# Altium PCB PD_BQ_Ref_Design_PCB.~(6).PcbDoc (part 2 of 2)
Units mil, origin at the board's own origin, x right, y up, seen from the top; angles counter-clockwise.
Board outline 2000 x 3000 mil, 4 copper layers (Top Layer, Signal Layer 1, Signal Layer 2, Bottom Layer), stack 61.2 mil thick; 108 components, 54 nets, 333 pads, 494 vias.
Unrouted connection lines stored in the file: 228.

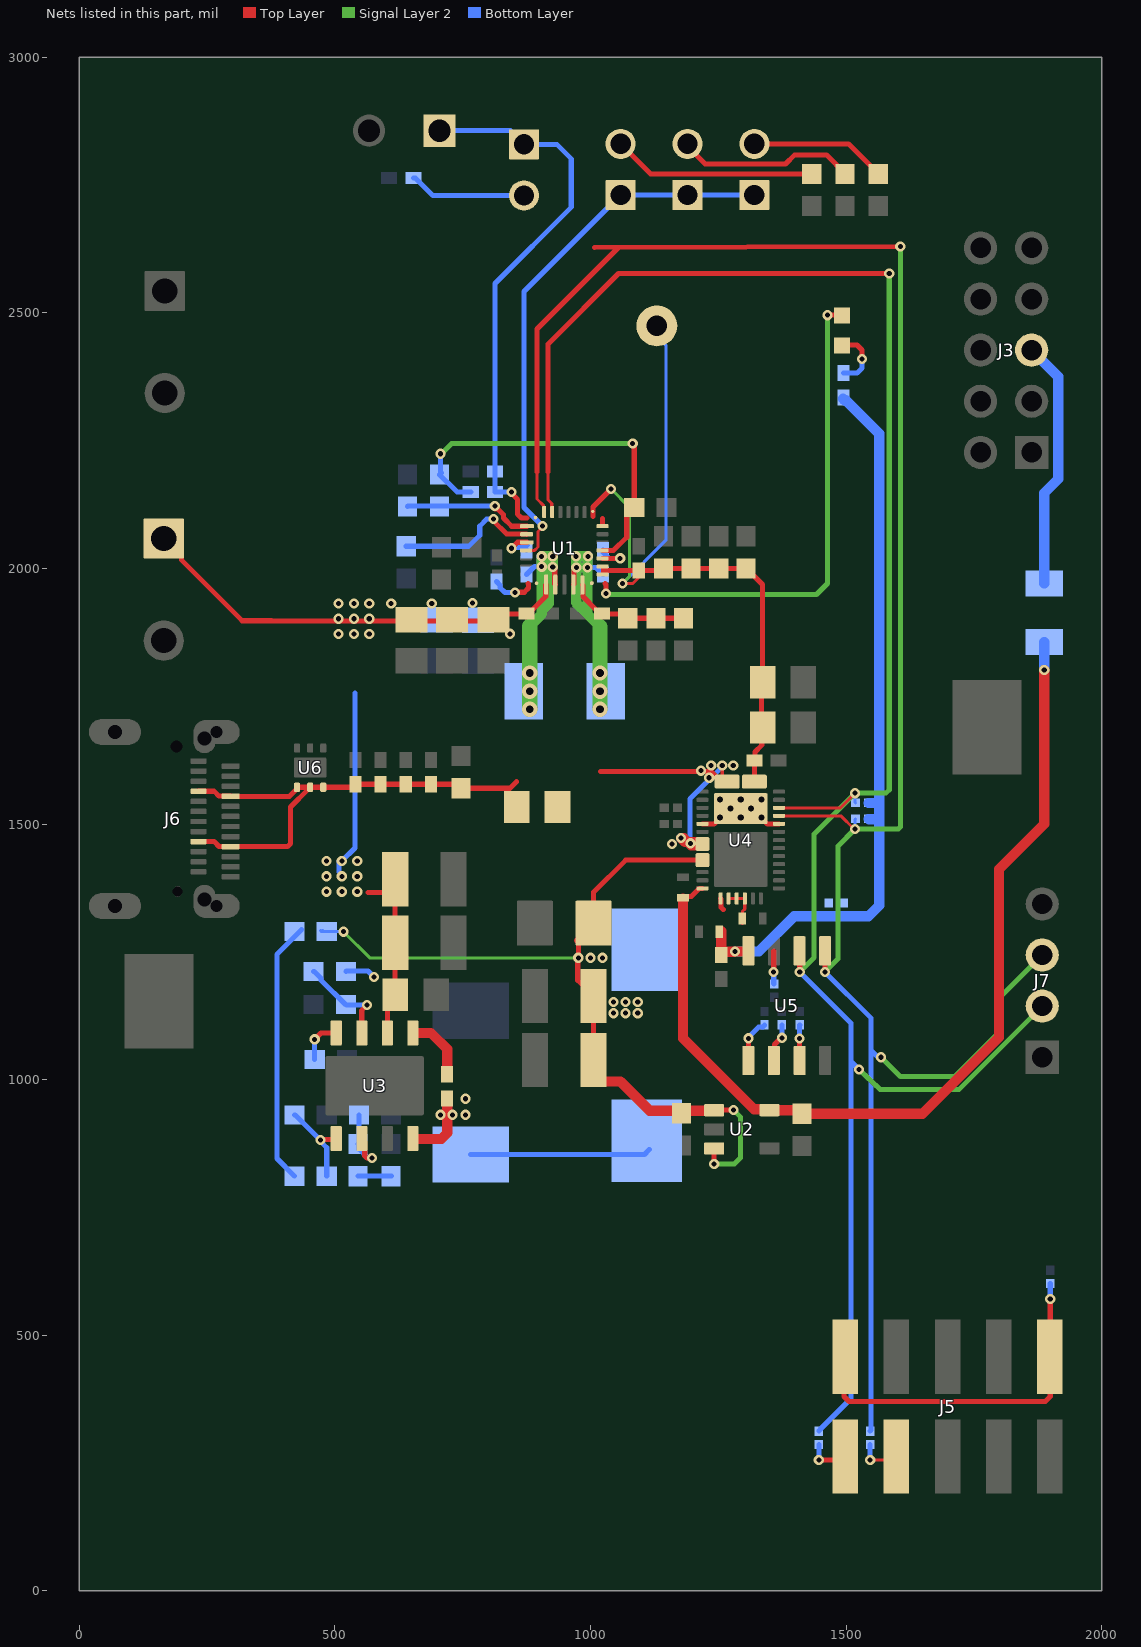
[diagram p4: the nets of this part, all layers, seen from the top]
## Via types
v1: diameter 20, hole 10, Top Layer to Bottom Layer, tented both sides, 445 vias
v2: diameter 23.62, hole 11.81, Top Layer to Bottom Layer, tented both sides, 24 vias
v3: diameter 30, hole 15, Top Layer to Bottom Layer, tented both sides, 12 vias
v4: diameter 19.68, hole 7.87, Top Layer to Bottom Layer, tented both sides, 10 vias
v5: diameter 20, hole 10, Top Layer to Bottom Layer, 3 vias

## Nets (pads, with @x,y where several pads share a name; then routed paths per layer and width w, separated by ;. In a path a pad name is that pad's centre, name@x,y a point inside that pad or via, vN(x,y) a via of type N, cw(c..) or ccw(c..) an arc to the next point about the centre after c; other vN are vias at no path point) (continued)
I2C_SCL: J7.2 R21.1 R24.2 R26.1 U1.14 U4.17 U5.6 | length 4180.7
  Top Layer w6: 917.32,2188.98 917.32,2133.86 924.38,2126.8 924.38,2111.07 U1.14@925.31,2110.14 ; U4.17@1368.91,1531.68 1489.12,1531.68 v1(1517.72,1560.27)
  Top Layer w10: 917.32,2188.98 917.32,2438.98 1055.12,2576.77 v1(1584.65,2576.77) ; v1(1409.45,1210.63) U5.6@1409.45,1251.5
  Signal Layer 2 w10: v1(1409.45,1210.63) 1437.32,1238.5 1437.32,1479.88 v1(1517.72,1560.27) 1577.99,1560.27 1584.65,1566.93 v1(1584.65,2576.77) ; v1(1525.59,1019.68) 1566.93,980.32 1720.47,980.32 J7.2@1883.86,1143.7
  Bottom Layer w6: v1(1517.72,1560.27) 1517.72,1542.13 R24.2@1518.5,1541.34
  Bottom Layer w10: v1(1409.45,1210.63) 1509.84,1110.24 1509.84,1033.46 ; R26.1@1446.85,312.2 1446.85,312.99 1450.12,316.26 1450.21,316.26 1509.84,375.9 1509.84,1033.46 ; v1(1525.59,1019.68) 1511.81,1033.46 1509.84,1033.46
I2C_SDA: J7.3 R22.1 R25.2 R27.1 U1.15 U4.16 U5.5 | length 4366.5
  Top Layer w6: 895.67,2188.98 895.67,2135.83 908.63,2122.87 908.63,2111.07 U1.15@909.57,2110.14 ; U4.16@1368.91,1515.93 1489.98,1515.93 1515.75,1490.16 v1(1517.72,1490.16)
  Top Layer w10: 895.67,2188.98 895.67,2468.5 1055.12,2627.95 ; 1007.87,2627.95 v1@1604.33,2629.92 ; v1(1458.66,1210.63) U5.5@1458.66,1251.5
  Signal Layer 2 w10: v1(1458.66,1210.63) 1484.25,1236.22 1484.25,1456.69 v1(1517.72,1490.16) 1602.36,1490.16 1606.3,1494.09 v1(1606.3,2629.92) ; v1(1568.5,1043.7) 1606.3,1005.91 1712.6,1005.91 1797.24,1090.55 1797.24,1157.09 J7.3@1883.86,1243.7
  Bottom Layer w6: v1(1517.72,1490.16) 1517.72,1509.05 R25.2@1518.5,1509.84
  Bottom Layer w10: v1(1458.66,1210.63) 1549.21,1120.08 1549.21,1057.09 ; R27.1@1547.24,312.2 1549.21,314.17 1549.21,1057.09 ; v1(1568.5,1043.7) 1562.6,1043.7 1549.21,1057.09
ILIM_HIZ: R4.1 R6.2 U1.17 | length 265.7
  Top Layer w10: v1@818.44,2116.46 812.99,2116.46 v1(812.99,2122.04) 830.16,2104.88 830.16,2098.5 846.08,2082.58 U1.17@876.1,2082.58
  Bottom Layer w10: R6.2@641.92,2121.06 642.9,2122.05 802.68,2122.05 v1(812.99,2122.04)
LDO_1V5: C37.1 U4.2 U4.3 U4.4 | length 83
  Top Layer w6: U4.2@1270.48,1354.51 U4.3@1286.23,1354.51 U4.4@1301.98,1354.51 1301.98,1333.47 1297.24,1328.74 1297.24,1305.43 C37.1@1296.93,1305.12
LDO_3V3: C36.1 C43.1 R2.2 R21.2 R22.2 R24.1 R25.1 U4.1 U5.8 | length 1507.2
  Top Layer w10: U4.1@1254.73,1354.51 1255.8,1353.45 1255.8,1336.72 1259.84,1332.68
  Top Layer w20: C43.1@1255.91,1244.09 1255.91,1248.03 C43.1@1257.72,1249.84 ; C36.1@1255.91,1290.2 1255.91,1249.84 C43.1@1257.72,1249.84 ; U5.8@1309.05,1251.89 1307.79,1250.63 v1(1282.76,1250.63) 1282.13,1250 1269.43,1250 1269.27,1249.84 C43.1@1257.72,1249.84
  Bottom Layer w20: v1@1283.46,1250.63 1329.37,1250.63 1398.43,1319.69 1468.5,1319.69 1498.03,1319.69 1527.56,1319.69 1544.09,1319.69 1564.96,1340.55 1564.96,1509.35 ; R2.2@1494.09,2331.69 1496.89,2328.9 1499.84,2328.9 1564.96,2263.78 1564.96,1541.91 ; R25.1@1544.49,1509.84 1544.98,1509.35 1564.96,1509.35 ; R24.1@1544.49,1541.34 1564.39,1541.34 1564.96,1541.91 ; 1564.96,1509.35 1564.96,1541.91
NetC1_1: C1.1 U1.4 | length 76.9
  Top Layer w10: U1.4@1023.74,2019.59 1058.09,2019.59 v1(1058.19,2019.69)
  Bottom Layer w10: C1.1@1024.72,2035.43 1024.72,2031.5 1036.64,2019.59 1058.09,2019.59 v1(1058.19,2019.69)
NetC1_2: C1.2 L1.1 U1.28 | length 640.5
  Top Layer w10: U1.28@966.65,1968.4 967.72,1969.47 967.72,1997.24 v1(972.44,2001.97)
  Signal Layer 2 w20: 1018.82,1885.83 994.42,1910.22 ; v1(972.44,2001.97) 972.44,2022.76 v1(971.57,2023.62) v1(995.2,2023.62) 994.09,2022.52 v1(994.09,2001.97) ; v1(972.44,2001.97) v1(994.09,2001.97) ; v1(972.44,2001.97) 972.44,1933.97 971.56,1933.09 994.42,1910.22 ; v1(994.09,2001.97) 994.42,2001.64 994.42,1910.22
  Signal Layer 2 w30: v3(1018.82,1724.41) 1018.82,1885.83
  Bottom Layer w10: v1(994.09,2001.97) 1010.94,2001.97 C1.2@1024.72,1988.19
  Bottom Layer w20: v1@971.57,2003.74 972.44,2002.87 v1(972.44,2001.97) v1(994.09,2001.97) 994.09,2022.52 v1(995.2,2023.62) v1(971.57,2023.62) v1@971.57,2003.74
  other v3: 1018.82,1759.84 1018.82,1795.44
NetC7_1: C7.1 U1.19 | length 77
  Top Layer w10: v1(845.59,2039.37) 857.3,2051.08 U1.19@875.71,2051.08
  Bottom Layer w10: v1(845.59,2039.37) 847.09,2040.87 869.68,2040.87 C7.1@875.12,2035.43 ; C7.1@870.35,2039.37 C7.1@877.17,2046.18
NetC7_2: C7.2 L1.2 U1.26 | length 624.4
  Top Layer w10: v1(926.3,2002.54) 926.3,2001.23 930.16,1997.37 930.16,1969.47 U1.26@931.22,1968.4
  Signal Layer 2 w20: 881.02,1887.04 904.65,1910.67 v1(904.65,2003.36) 925.47,2003.36 v1(926.3,2002.54) ; 904.65,1917.32 918.43,1931.1 918.43,1994.66 v1(926.3,2002.54) ; v1@904.65,2004.35 v1(904.65,2023.62) v1(926.3,2023.62) v1(926.3,2002.54)
  Signal Layer 2 w30: v3(881.02,1724.41) v3(881.02,1759.84) v3(881.02,1795.3) 881.02,1887.04
  Bottom Layer w10: C7.2@875.12,1988.19 890.87,2003.94 891.44,2003.36 v1(904.65,2003.36)
  Bottom Layer w20: v1(904.65,2003.36) 925.47,2003.36 v1(926.3,2002.54) v1(926.3,2023.62) v1(904.65,2023.62) v1(904.65,2003.36)
NetC22_1: C22.1 U1.24 | length 87.7
  Top Layer w10: v1(852.36,1952.76) 853.01,1953.4 870.73,1953.4 878.91,1961.58 878.91,1969.52 877.95,1970.47
  Bottom Layer w10: C22.1@816.06,1974.41 822.87,1967.6 822.87,1962.55 832.67,1952.76 v1(852.36,1952.76)
NetC25_1: C25.1 U3.1 | length 129.4
  Top Layer w20: U3.1@652.76,1091.26 688.27,1091.26 719.74,1059.78 C25.1@719.74,1010.38
NetC25_2: C25.2 D2.1 L2.1 U3.8 | length 493.1
  Top Layer w20: U3.8@652.76,884.57 652.87,884.57 653.58,883.86 708.03,883.86 719.74,895.57 C25.2@719.74,963.14
  Bottom Layer w10: D2.1@765.75,853.6 1105.57,853.6 L2.1@1115.16,863.19
  other v1: 706.69,931.1 730.32,931.1 755.91,931.1 755.91,962.6
NetC32_1: C32.1 C34.1 U3.6 | length 164.6
  Top Layer w10: U3.6@552.76,884.57 558.58,878.74 558.58,850.87 562.99,846.46 v1(572.83,846.46)
  Bottom Layer w10: C32.1@546.79,874.02 C32.1@546.79,872.56 ; C34.1@547.24,931.1 547.24,875.98 C32.1@545.28,874.02 C32.1@546.79,872.56 ; C32.1@547.98,864.41 549.51,869.93 C32.1@546.79,872.56 ; v1(572.83,846.46) 565.06,846.46 546.79,864.74 C32.1@546.79,872.56
NetC32_2: C32.2 R17.2 | length 65.9
  Bottom Layer w10: C32.2@545.28,811.02 R17.2@611.22,811.02
NetC33_1: C33.1 U3.4 | length 86.7
  Top Layer w10: v1(460.63,1078.74) 473.15,1091.26 U3.4@502.76,1091.26
  Bottom Layer w10: C33.1@460.63,1039.37 v1(460.63,1078.74)
NetC44_1: C44.1 C45.2 C46.2 C47.2 C48.2 J6.A4 J6.A9 J6.B4 J6.B9 L3.1 U6.4 U6.5 U6.6 | length 961.1
  Top Layer w10: J6.B4@233.27,1465.55 264.02,1465.55 273.54,1456.02 295.94,1456.02 J6.A9@296.26,1455.71 311.38,1455.71 407.53,1455.71 413.39,1461.57 413.39,1533.46 447.91,1567.99 450.87,1567.99 451.77,1568.9 U6.5@451.77,1571.85 ; J6.B9@233.27,1563.98 264.02,1563.98 273.54,1554.45 295.94,1554.45 J6.A4@296.26,1554.13 411.42,1554.13 426.18,1568.9 U6.4@426.18,1571.85 447.91,1571.85 U6.5@451.77,1571.85 ; 855.67,1582.68 842.87,1569.88 C44.1@747.05,1569.88 739.17,1577.76 C48.2@687.99,1577.76 C47.2@638.78,1577.76 C46.2@589.57,1577.76 C45.2@540.35,1577.76 534.45,1571.85 U6.6@477.36,1571.85 U6.5@451.77,1571.85
NetD1_1: D1.1 R2.1 | length 119.8
  Top Layer w10: D1.1@1492.13,2436.02 1493.11,2437.01 1521.65,2437.01 1531.5,2427.17 v1(1531.5,2409.45)
  Bottom Layer w10: R2.1@1495.08,2381.89 1521.65,2381.89 1531.5,2391.73 v1(1531.5,2409.45)
NetJ3_5: J3.5 R11.1 | length 489.2
  Bottom Layer w20: J3.5@1863.19,2426.97 1915,2375.16 1915,2174.84 1887.8,2147.64 R11.1@1887.8,1970.47
NetJ5_1: J5.1 R26.2 | length 85
  Top Layer w10: v1(1446.85,255.91) 1491.67,255.91 J5.1@1498.64,262.87
  Bottom Layer w10: v1(1446.85,255.91) R26.2@1446.85,286.22
NetJ5_2: J5.2 J5.10 R29.2 | length 712.5
  Top Layer w10: J5.2@1498.64,457.75 1496.16,455.27 1496.16,379.83 1505.91,370.08 1889.76,370.08 1899.51,379.83 1899.51,456.88 J5.10@1898.64,457.75 1899.61,458.72 v1(1899.61,570.87)
  Bottom Layer w10: v1(1899.61,570.87) R29.2@1899.61,601.18
NetJ5_3: J5.3 R27.2 | length 84.6
  Top Layer w6: v1(1547.24,255.91) 1591.67,255.91 J5.3@1598.64,262.87
  Bottom Layer w10: v1(1547.24,255.91) R27.2@1547.24,286.22
NetJP1_2: JP1.2 R8.2 | length 398.4
  Top Layer w10: JP1.2@1059.06,2830.51 1117.91,2771.65 R8.2@1433.07,2771.65
NetJP2_2: JP2.2 R9.2 | length 350.8
  Top Layer w10: JP2.2@1189.96,2830.51 1189.96,2825.79 1224.76,2790.98 1381.73,2790.98 1399.81,2809.06 1461.61,2809.06 1498.03,2772.64 R9.2@1498.03,2771.65
NetJP3_2: JP3.2 R10.2 | length 267.1
  Top Layer w10: JP3.2@1320.87,2830.51 1505.12,2830.51 1562.99,2772.64 R10.2@1562.99,2771.65
NetJP4_2: JP4.2 R7.2 | length 230.7
  Bottom Layer w10: R7.2@653.54,2763.78 657.48,2763.78 691.73,2729.53 JP4.2@870.08,2729.53
NetR1_2: R1.2 U1.18 | length 281.9
  Top Layer w10: v1(810.16,2096.46) 810.16,2093.39 835.97,2067.58 874.37,2067.58 U1.18@875.12,2066.83
  Bottom Layer w10: R1.2@639.76,2043.31 761.81,2043.31 783.46,2064.96 783.46,2082.58 783.41,2082.63 797.24,2096.46 v1(810.16,2096.46)
NetR12_1: R12.1 R14.2 | length 516.5
  Bottom Layer w10: R14.2@421.26,811.02 386.81,845.47 386.81,1245.08 R12.1@435.04,1293.31
NetR13_1: R13.1 R15.2 U3.3 | length 192.6
  Top Layer w10: U3.3@552.76,1091.26 552.76,1135.43 v1(562.99,1145.67)
  Bottom Layer w10: R13.1@458.66,1211.61 459.65,1211.61 473.35,1197.91 473.35,1193.98 520.67,1146.65 R15.2@521.65,1146.65 522.64,1145.67 v1(562.99,1145.67)
NetR14_1: R14.1 R16.2 U3.5 | length 179
  Top Layer w10: v1(471.95,881.89) 472.82,882.77 500.95,882.77 U3.5@502.76,884.57
  Bottom Layer w10: R16.2@421.26,931.1 422.24,931.1 471.46,881.89 v1(471.95,881.89) 471.95,879.18 484.25,866.88 R14.1@484.25,811.02
NetR28_2: R28.2 | length 65.4
  Top Layer w10: v1(1358.27,1210.63) 1358.66,1211.02 1358.66,1251.5 1359.05,1251.89
  Bottom Layer w10: v1(1358.27,1210.63) 1358.76,1210.14 1358.76,1187.7 R28.2@1359.25,1187.2
NetR30_2: R30.2 U5.1 | length 87.4
  Top Layer w10: U5.1@1309.05,1037.33 v1(1309.06,1080.71)
  Bottom Layer w10: v1(1309.06,1080.71) 1309.06,1082.68 1329.41,1103.03 1337.28,1103.03 1340.55,1106.3 R30.2@1340.55,1107.09
NetR31_2: R31.2 U5.2 | length 76.5
  Top Layer w10: U5.2@1359.05,1037.33 1360.24,1038.51 1360.24,1068.9 1373.03,1081.69 v1(1375,1081.69)
  Bottom Layer w10: v1@1374.51,1082.18 R31.2@1374.51,1106.59
NetR32_2: R32.2 U5.3 | length 69.9
  Top Layer w10: U5.3@1409.05,1037.33 1409.14,1037.42 1409.14,1080.42 v1(1409.23,1080.51)
  Bottom Layer w10: v1(1409.23,1080.51) 1409.34,1080.62 1409.34,1106.98 R32.2@1409.45,1107.09
NetU4_15: U4.15 U4.30 U4.40 | length 233.7
  Top Layer w10: U4.30@1219.3,1500.18 1242.13,1500.18 U4.40@1272.06,1530.1 ; U4.40@1254.14,1512.19 U4.40@1272.06,1530.1 ; U4.15@1368.91,1500.18 1346.07,1500.18 ; U4.40@1272.06,1530.1 v2(1274.02,1530.1) U4.40@1294.1,1530.1 v2(1314.18,1530.1) 1316.15,1530.1 1346.07,1500.18 ; 1346.07,1500.18 1334.06,1512.19 1346.07,1500.18
  other v2: 1253.95,1512.39 1294.1,1512.39 1334.26,1512.39 1253.95,1547.82 1294.1,1547.82 1334.26,1547.82
P3V3: C24.2 C35.1 R11.2 U2.5 U4.38 | length 1869
  Top Layer w10: C35.1@1181.1,1355.98 1183.6,1358.48 1197.84,1358.48 1213.55,1374.2 U4.38@1219.3,1374.2
  Top Layer w20: C35.1@1181.1,1354.33 1181.1,1080.71 1319.94,941.87 1348.58,941.87 U2.5@1350.39,940.06 ; U2.5@1352.2,940.06 1406.67,940.06 C24.2@1413.55,933.17 1649.7,933.17 1799.21,1082.68 1799.21,1411.42 1887.8,1500 v1(1887.8,1801.18)
  Bottom Layer w20: v1(1887.8,1801.18) R11.2@1887.8,1856.3
PMID: C8.2 C9.2 C10.2 C11.1 U1.29 | length 238.5
  Top Layer w10: U1.29@984.37,1967.42 985.28,1966.51 985.28,1944.96 1012.01,1918.23 1012.01,1916.26 1017.83,1910.43 1065.08,1910.43 C10.2@1072.95,1902.56 C9.2@1128.07,1902.56 C8.2@1182.2,1902.56
PP5V: C23.2 C26.1 C27.1 C28.1 L2.2 R12.2 U2.1 U2.3 U4.34-35 | length 1669.2
  Top Layer w10: C28.1@1005.91,1038.39 1006.3,1038.78 1006.3,1163.39 975.32,1194.37 975.32,1237.13 v1(976.38,1238.19) 976.38,1268.31 972.44,1272.24 C26.1@1006.3,1306.1 ; C26.1@1023.03,1289.37 C26.1@1006.3,1306.1 ; U4.34-35@1219.3,1429.31 1069.08,1429.31 1006.3,1366.54 C26.1@1006.3,1306.1 ; v1(1242.13,834.65) U2.3@1242.13,865.25 ; U2.1@1242.13,940.06 1242.29,940.22 1279.99,940.22 v1(1280.16,940.39)
  Top Layer w20: C28.1@1005.91,1038.39 1005.91,1011.65 1021.5,996.06 1059.06,996.06 1116.14,938.98 1173.32,938.98 C23.2@1178.15,934.15 1182.98,938.98 1241.05,938.98 U2.1@1242.13,940.06
  Signal Layer 2 w6: v1(516.96,1289.37) 568.14,1238.19 v1(976.38,1238.19)
  Signal Layer 2 w10: v1(1242.13,834.65) 1281.5,834.65 1293.31,846.46 1293.31,927.17 1280.16,940.31 v1(1280.16,940.39)
  Bottom Layer w6: R12.2@472.44,1291.34 474.41,1289.37 476.38,1291.34 478.35,1289.37 v1(516.96,1289.37)
  other v1: 1045.28,1129.92 1068.9,1129.92 1092.52,1129.92 1045.28,1151.57 1068.9,1151.57 1092.52,1151.57 1000,1238.19 1023.62,1238.19
PPHV: C2.2 C3.2 C4.2 C5.2 C6.1 C38.1 C39.1 C40.1 TP1.1 U1.2 U1.3 U1.8 U1.9 U4.20-21-22 | length 1633.6
  Top Layer w6: 1022.76,2098.43 1023.74,2097.44 ; U1.2@1023.74,1988.09 1023.74,1996.06 U1.3@1023.74,2003.84 ; v1(1062.99,1970.47) 1082.8,1970.47 1101.5,1989.17 C6.1@1094.61,1996.06
  Top Layer w10: 1005.04,2101.41 1005.04,2120.08 ; U1.9@1005.04,2111.61 1005.04,2120.08 ; U1.8@1023.74,2084.65 1023.74,2097.44 ; 1026.69,1996.06 1049.59,1996.06 1049.9,1995.75 1066.47,1995.75 1066.79,1996.06 C6.1@1094.61,1996.06 1138.9,1996.06 C5.2@1142.83,2000 C4.2@1196.97,2000 C3.2@1251.1,2000 1305.24,2000 1336.78,1968.46 1336.78,1799.14 1334.98,1797.34 1334.98,1712.36 1336.78,1710.56 1335.27,1709.04 1335.27,1654.17 1322.06,1640.96 1322.06,1621.33 1320.74,1620 U4.20-21-22@1320.74,1582.86 ; v1(1040.47,2155.51) 1005.04,2120.08
  Signal Layer 2 w6: v1(1040.47,2155.51) 1076.19,2119.8 1076.19,1983.67 v1(1062.99,1970.47)
  Bottom Layer w6: v1(1062.99,1970.47) 1147.64,2055.12 1147.64,2436.67 1129.92,2454.39 TP1.1@1129.92,2474.41
PROG: JP1.1 JP2.1 JP3.1 U1.20 | length 1073.5
  Top Layer w6: U1.20@874.13,2035.33 890.9,2035.33 897.39,2041.83 897.39,2072.16 906.44,2081.21 v1(906.44,2082.85)
  Bottom Layer w10: v1(906.44,2082.85) 870.08,2119.21 870.08,2541.54 JP1.1@1059.06,2730.51 JP2.1@1189.96,2730.51 JP3.1@1320.87,2730.51
REGN: C18.1 R3.2 R4.2 U1.5 | length 752.8
  Top Layer w10: U1.5@1023.74,2035.33 1045.41,2035.33 1071.06,2060.99 1071.06,2105.39 1084.76,2119.09 C18.1@1085.75,2119.09 1085.75,2241.02 v1(1082.68,2244.09)
  Signal Layer 2 w10: v1(706.69,2224.41) 708.66,2224.41 728.35,2244.09 v1(1082.68,2244.09)
  Bottom Layer w10: R4.2@704.78,2184.06 R4.2@704.78,2183.07 ; v1(706.69,2224.41) 706.69,2188.92 708.66,2186.96 R4.2@704.78,2183.07 ; R3.2@765.87,2149.61 739.29,2149.61 719.53,2169.37 718.48,2169.37 R4.2@704.78,2183.07
STAT: D1.2 U1.1 | length 1022.6
  Top Layer w10: 1028.73,1970.41 1030.64,1968.49 v1(1030.64,1950.82) ; v1(1463.93,2495.43) 1488.83,2495.43 D1.2@1492.13,2492.13
  Signal Layer 2 w10: v1(1030.64,1950.82) 1032.56,1948.91 1039.63,1948.91 1039.72,1948.82 1442.32,1948.82 1463.93,1970.42 v1@1463.93,2500
SYS: C12.1 C13.1 C14.1 C15.1 C16.1 C17.1 C29.1 C30.1 C31.1 J1.1 R13.2 U1.25 U3.2 | length 1655.4
  Top Layer w10: J1.1@165.35,2058.66 199.72,2024.29 199.72,2016.81 318.9,1897.64 376.08,1897.64 376.44,1897.28 493.23,1897.28 507.4,1897.28 537.4,1897.28 v1@573.94,1897.28 ; 564.96,1366.14 C29.1@618.11,1366.14 ; v1@567.4,1897.28 v1@573.94,1897.28 ; U3.2@602.76,1091.26 602.76,1150.52 C31.1@618.28,1166.04 618.11,1166.21 C30.1@618.11,1267.72 ; C30.1@614.17,1271.65 C30.1@618.11,1267.72 ; C29.1@618.11,1391.73 C29.1@618.11,1366.14 ; U1.25@913.5,1968.4 912.6,1967.5 912.6,1944.96 888.82,1921.18 878.07,1910.43 827.24,1910.43 814.09,1897.28 733.39,1897.28 653.66,1897.28 v1@573.94,1897.28 ; C30.1@618.11,1267.72 C29.1@618.11,1366.14
  Bottom Layer w10: 508,1406 v1@508,1427.64 ; v1(513.78,1427.64) 539.37,1453.23 539.37,1756.08 ; R13.2@521.65,1211.61 522.64,1212.6 564.96,1212.6 v1(576.77,1200.79)
  other v1: 483.78,1367.64 513.78,1367.64 543.78,1367.64 483.78,1397.64 513.78,1397.64 543.78,1397.64 483.78,1427.64 543.78,1427.64 507.4,1871.57 537.4,1871.57 567.4,1871.57 842.52,1872.05 507.4,1901.57 537.4,1901.57 567.4,1901.57 610.24,1931.1 689.72,1931.19 507.4,1931.57 537.4,1931.57 567.4,1931.57 769.45,1932.47
TS: J4.1 JP4.1 R3.1 R5.2 U1.16 | length 1096.9
  Top Layer w10: v1(845.59,2149.61) 845.59,2146.9 857.4,2135.09 857.4,2106.12 865.09,2098.43 876.04,2098.43
  Bottom Layer w10: J4.1@704.72,2856.3 843.31,2856.3 JP4.1@870.08,2829.53 934.25,2829.53 962.6,2801.18 962.6,2706.69 813.11,2557.2 R5.2@813.11,2189.96 R3.1@813.11,2149.61 v1(845.59,2149.61)
VBUS: L3.2 U4.23-24-25 U4.32-33 | length 575.9
  Top Layer w6: v1@1194.88,1460.63 1219.12,1460.63 U4.32-33@1219.3,1460.81 ; v1(1257.87,1614.17) 1257.87,1592.95 1267.72,1583.11 U4.23-24-25@1267.47,1582.86
  Top Layer w10: 1019.68,1602.36 1216.54,1602.36 1237.08,1602.36 1256.58,1582.86 U4.23-24-25@1267.47,1582.86
  Top Layer w20: v1@1204.72,1458.09 1197.42,1458.09 v1@1190.92,1464.59 ; U4.32-33@1219.3,1460.81 1215.52,1464.59 v1@1190.92,1464.59 ; v1@1190.92,1464.59 1183.07,1472.44 v1(1177.17,1472.44) 1185.02,1464.59 v1@1190.92,1464.59
  Bottom Layer w10: v1@1194.88,1460.63 1194.88,1549.21 1257.87,1612.2 v1(1257.87,1614.17)
  other v1: 1159.45,1460.63 1195.85,1462.13 1232.28,1590.55 1216.54,1604.33 1236.22,1614.17 1279.53,1614.17
pads on no net: J3.1 J3.2 J3.3 J3.4 J3.7 J3.8 J5.4 J5.5 J5.6 J5.7 J5.8 J5.9 J6.A2 J6.A3 J6.A8 J6.A10 J6.A11 J6.ALIGN1 J6.ALIGN2 J6.B2 J6.B3 J6.B8 J6.B10 J6.B11 J7.1 U1.6 U1.7 U1.12 U1.21 U2.4 U3.9@577.76,987.91 U4.6 U4.7 U4.13 U4.18 U4.19 U4.36 U4.37 U5.C U6.7@434.06,1610.24 U6.7@469.49,1610.24

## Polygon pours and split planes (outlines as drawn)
NetC22_1 on Top Layer "TOP_LAYER_NETC22_1_P111" (solid, remove dead copper, pour order 111): 898.87,1975.98 848.82,1975.98 848.43,1976.38 848.43,1946.85 899.61,1946.85 898.87,1947.59
STAT on Top Layer "TOP_LAYER_STAT_P109" (solid, remove dead copper, pour order 109): 998.03,1975.98 998.03,1950.2 999.41,1948.82 1035.43,1948.82 1035.43,1975.92 1034.97,1976.38 1034.3,1975.7 998.73,1975.7
PPHV on Top Layer "TOP_LAYER_PPHV_P107" (solid, remove dead copper, pour order 107): 1000.69,2094.96 1000.27,2095.39 1000.27,2139.76 1039.37,2160.39 1040.32,2159.45 1049.21,2159.45 1049.21,2147.64 1033.46,2131.89 1033.46,2080.71 1035.23,2078.94 1013.78,2078.94 1013.78,2092.52 1011.33,2094.96
TS on Top Layer "TOP_LAYER_TS_P105" (solid, remove dead copper, pour order 105): 852.36,2131.89 885.71,2131.89 897.64,2119.97 897.64,2094.96 863.45,2094.96 863.18,2094.69 853.53,2104.33 852.36,2104.33
NetC1_2 on Top Layer "TOP_LAYER_NETC1_2_P103" (solid, remove dead copper, pour order 103): 960.63,2033.46 960.63,1992.13 1007.87,1992.13 1007.87,2033.46
NetC7_2 on Top Layer "TOP_LAYER_NETC7_2_P101" (solid, remove dead copper, pour order 101): 893.7,2033.46 893.7,1994.09 937.01,1994.09 937.01,2033.46
BAT on Top Layer "TOP_LAYER_BAT_P099" (solid, pour order 99): 769.68,2000 836.61,2000 836.61,1986.22 834.65,1984.25 769.68,1984.25 769.68,1999.76 769.45,2000
GND on Top Layer "tgaTOP_LAYER_GND_P081" (solid, pour order 97): 8.19,7.05 2008.19,7.05 2008.19,3007.05 8.19,3007.05
VBUS on Top Layer "Top Layer-VBUS" (solid, pour order 95): 1098.43,1598.43 1200.79,1598.43 1230.32,1568.9 1291.34,1568.9 1291.34,1663.38 1019.68,1663.39 950.79,1594.49 905.51,1594.49 905.51,1468.5 968.5,1468.5
NetC44_1 on Top Layer "Top Layer-NetC44_1" (solid, pour order 89): 427.17,1468.5 885.83,1468.5 885.83,1511.81 885.83,1594.49 787.4,1594.49 500,1594.49 488.19,1582.68 415.35,1582.68 391.73,1559.06 324.8,1559.05 324.8,1450.79 409.45,1450.79
SYS on Top Layer "Top Layer-SYS" (solid, pour order 40): 541.34,1196.85 590.55,1147.64 590.55,1102.36 614.17,1102.36 645.67,1133.86 649.61,1133.86 649.61,1448.82 458.66,1448.82 458.66,1338.58 541.34,1338.58
NetC25_2 on Top Layer "Top Layer-NetC25_2" (solid, pour order 85): 687.01,874.02 722.44,874.02 771.65,923.23 771.65,978.35 687.01,978.35
SYS on Top Layer "Top Layer-SYS 1" (solid, pour order 72): 255.91,1856.3 859.16,1856.3 900.5,1897.64 900.5,1944.88 551.18,1944.88 529.53,1966.54 297.24,1966.54 218.5,2045.28 218.5,2114.17 196.85,2114.17 112.2,2114.17 112.2,2000
LDO_1V5 on Top Layer "NONET_L-01_P-001" (solid, pour order 77): 1267.72,1342.52 1267.72,1366.14 1305.12,1366.14 1305.12,1303.15 1289.37,1303.15 1289.37,1320.87
AGND on Top Layer "NONET_L-01_P-001" (solid, pour order 76): 1401.57,2736.22 1598.43,2736.22 1598.43,2657.48 1401.57,2657.48
AGND on Top Layer "NONET_L-01_P-001" (solid, pour order 75): 946.85,2098.43 935.04,2098.43 935.04,2159.45 994.09,2159.45 994.09,2098.43 966.54,2098.43 966.54,2125.98 946.85,2125.98
BAT on Top Layer "Top Layer-BAT" (solid, pour order 66): 559.1,1956.65 649.61,1956.69 826.77,1956.69 854.33,1984.25 883.86,1984.25 883.86,2007.87 846.46,2007.87 826.77,1988.19 797.24,1988.19 785.43,2000 688.98,2000 521.65,2167.32 521.65,2250 374.02,2397.64 118.11,2397.64 118.11,2289.37 328.74,2289.37 413.39,2204.72 413.39,2102.36
PPHV on Top Layer "Top Layer-PPHV" (solid, pour order 51): 1269.68,1568.9 1346.46,1568.9 1346.46,1649.61 1377.95,1681.1 1377.95,1850.39 1377.95,2033.46 1043.31,2033.46 1043.31,1956.69 1232.28,1956.69 1269.68,1919.29
no net on Top Layer "NONET_L-01_P-001" (solid, pour order 49): 1377.95,1850.39
no net on Top Layer "NONET_L-01_P-001" (solid, pour order 48): 1377.95,1830.71
PPHV on Top Layer "NONET_L-01_P-001" (solid, pour order 14): 1090.98,2007.87 1116.42,2033.31 1324.71,2033.31 1324.88,1978.35 1012.91,1978.35 1012.91,2007.87
REGN on Top Layer "NONET_L-01_P-001" (solid, pour order 32): 1020.79,2031.5 1048.35,2031.5 1075.91,2059.06 1075.91,2070.87 1105.43,2100.39 1105.43,2137.8 1066.06,2137.8 1046.38,2118.11 1046.38,2049.21 1036.54,2039.37 1020.79,2039.37
PMID on Top Layer "NONET_L-01_P-001" (solid, pour order 42): 999.13,1944.88 1232.28,1944.88 1232.28,1870.08 1026.69,1870.08 999.13,1897.64
P3V3 on Top Layer "NONET_L-01_P-001" (solid, pour order 30): 1206.69,1377.95 1192.91,1364.17 1192.91,1348.43 1200.79,1348.43 1222.44,1370.08 1222.44,1377.95
VBUS on Top Layer "NONET_L-01_P-001" (solid, pour order 20): 1212.6,1446.85 1212.6,1474.41 1194.88,1474.41 1183.07,1486.22 1143.7,1486.22 1143.7,1446.85
LDO_1V5 on Top Layer "NONET_L-01_P-001" (solid, pour order 31): 1305.12,1293.31 1305.12,1358.27 1267.72,1358.27 1267.72,1342.52 1287.4,1342.52 1287.4,1293.31
LDO_3V3 on Top Layer "NONET_L-01_P-001" (solid, pour order 29): 1259.84,1350.39 1265.75,1344.49 1265.75,1291.34 1246.06,1291.34 1246.06,1318.9 1246.06,1350.39
PP5V on Top Layer "NONET_L-01_P-001" (solid, pour order 28): 1257.87,1354.33
PP5V on Top Layer "Top Layer-PP5V" (solid, pour order 17): 964.57,964.57 1104.33,964.57 1104.33,1379.92 1139.76,1415.35 1232.28,1415.35 1232.28,1442.91 1151.57,1442.91 1131.71,1462.78 1033.65,1462.78 1011.81,1440.94 964.57,1393.7
NetC1_2 on Bottom Layer "NONET_L-01_P-001" (solid, pour order 44): 994.09,1706.69 994.09,1811.02 1038.5,1811.02 1038.5,1706.69
NetC7_2 on Bottom Layer "NONET_L-01_P-001" (solid, pour order 43): 907.48,1706.69 907.48,1811.02 861.34,1811.02 861.34,1706.69
GND on Bottom Layer "BOTTOM_LAYER_GND_P090" (solid, remove dead copper, pour order 90): -15.68,11.67 1984.32,11.67 1984.32,3011.67 -15.68,3011.67
SYS on Bottom Layer "Top Layer-SYS 1" (solid, pour order 87): 494.09,1856.3 859.16,1856.3 900.5,1897.64 900.5,1944.88 551.18,1944.88 529.53,1966.54 494.09,1966.54
SYS on Bottom Layer "Bottom Layer-SYS" (solid, pour order 74): 604.33,1551.18 604.33,1702.76 604.33,1946.85 494.09,1946.85 494.09,1653.54 494.09,1590.55 458.66,1555.12 458.66,1338.58 568.9,1338.58 568.9,1515.75
NetC25_2 on Bottom Layer "Bottom Layer-NetC25_2" (solid, pour order 84): 687.01,795.28 954.72,795.28 1181.1,795.28 1181.1,911.42 771.65,911.42 771.65,978.35 687.01,978.35
NetU4_15 on Bottom Layer "NONET_L-01_P-001" (solid, pour order 78): 1241.94,1561.02 1241.94,1499.2 1346.14,1499.2 1346.47,1561.02
no net on Bottom Layer "NONET_L-01_P-001" (solid, pour order 37): 533.46,2041.34
PP5V on Bottom Layer "NONET_L-01_P-001" (solid, pour order 22): 964.57,1334.65 964.57,1116.14 1179.13,1116.14 1179.13,1334.65
VBUS on Bottom Layer "NONET_L-01_P-001" (solid, pour order 21): 1206.69,1446.85 1151.57,1446.85 1151.57,1561.02 1216.54,1625.98 1291.34,1625.98 1291.34,1568.9 1232.28,1568.9 1206.69,1543.31
no net on Signal Layer 2 "SIGNAL_LAYER_2_NONET_P083" (solid, pour order 83): 0,0 2000,0 2000,3000 0,3000
NetU4_15 on Signal Layer 2 "NONET_L-01_P-001" (solid, pour order 80): 1242.13,1559.66 1242.13,1500 1346.33,1500.18 1346.45,1559.66
NetC7_2 on Signal Layer 2 "NONET_L-01_P-001" (solid, pour order 45): 894.8,1887.8 867.24,1887.8 867.24,1919.29 894.8,1946.85 894.8,2023.62 936.14,2023.62 936.14,1931.1
NetC1_2 on Signal Layer 2 "NONET_L-01_P-001" (solid, pour order 46): 1005.04,1887.8 1032.6,1887.8 1032.6,1919.29 1005.04,1946.85 1005.04,2023.62 963.7,2023.62 963.7,1931.1
GND on Signal Layer 1 "SIGNAL_LAYER_1_GND_P082" (solid, pour order 82): 0,0 2000,0 2000,3000 0,3000
NetU4_15 on Signal Layer 1 "NONET_L-01_P-001" (solid, pour order 79): 1242.13,1561.02 1346.46,1561.02 1346.07,1560.64 1346.07,1500.18 1242.13,1500.18

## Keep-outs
Keep-Out Layer:
  text ".Layer_Name" at 577,-858.49 h60

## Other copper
Top Layer:
  pour cut-out: 1000,1698.82 1000,1818.9 899.61,1818.9 899.61,1698.82
  text ".Layer_Name" at 577,-858.49 h60
Signal Layer 1:
  pour cut-out: 854.33,1820.87 1045.28,1820.87 1045.28,1698.82 856.3,1698.82
Signal Layer 2:
  pour cut-out: 854.33,1858.27 1045.28,1858.27 1045.28,1696.85 856.3,1696.85
Bottom Layer:
  pour cut-out: 854.33,1822.83 854.33,1696.85 1045.28,1696.85 1045.28,1822.83
  text ".Layer_Name" at 577,-858.49 h60

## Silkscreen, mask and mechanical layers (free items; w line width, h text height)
Top Overlay:
  lines w5: 386.81,1665.35 386.81,1773.62 386.81,2218.5 1237.2,2218.5 1492.13,2218.5 1492.13,765.75 386.81,765.75 386.81,944.88 386.81,1668.31 ; 830.71,1694.88 846.46,1710.63 860.24,1724.41 860.24,1866.14 874.02,1879.92 ; 1027.56,1879.92 1037.4,1870.08 1037.4,1724.41 1062.99,1698.82 1069.88,1691.93 ; 1114.17,1964.57 1127.95,1950.79 1242.13,1950.79 ; 1183.07,2098.43 1204.72,2120.08 ; 1214.57,2098.43 1238.19,2122.05 ; 1261.81,2098.43 1287.4,2124.02 ; 1314.96,2100.39 1340.55,2125.98 ; 1204.72,2120.08 1204.72,2120.08
  text "'.PRJ_Number'.PCB_Rev" at 1421.26,2881.89 h108.27
  text "up to 5A" at 43.31,2694.88 h60
  text "EXT_TS" at 542.43,2647.52 h60
  text "2S" at 1041.71,2630.06 h60
  text "4S" at 1306.21,2629.05 h60
  text "3S" at 1173.61,2628.46 h60
  text "TS" at 849.52,2623.14 h60
  text "GND" at 426.07,2528.65 h60 r90
  text "STAT" at 1296.37,2487.32 h60
  text "PPHV" at 1058.18,2314.09 h60
  text "BATT" at 437.88,2296.37 h60 r90
  text "up to 10A" at 53.15,2185.22 h60
  text "SYS" at 441.82,2010.94 h60 r90
  text "USB2ANY" at 1689.09,1908.57 h60
  text "Connector" at 1622.16,1854.44 h60
  text "GND" at 439.85,1804.24 h60 r90
  text "GND" at 1745.19,1463.69 h60
  text "GND" at 79.83,927.28 h60
  text "Aardvark" at 1655.62,626.09 h60
  text "Connector" at 1622.16,566.06 h60
  text "Total Solution Size" at 391.84,548.34 h60
  text "USB-PD-CHG-EVM-01" at 358,328.74 h108
  text ".Layer_Name" at 577,-858.49 h60
Bottom Overlay:
  text ".Layer_Name" at 577,-858.49 h60
Top Paste:
  text ".Layer_Name" at 577,-858.49 h60
Bottom Paste:
  text ".Layer_Name" at 577,-858.49 h60
Top Solder:
  text ".Layer_Name" at 577,-858.49 h60
  text ".Layer_Name" at 577,-858.49 h60
Bottom Solder:
  text ".Layer_Name" at 577,-858.49 h60
Drill Guide:
  text ".Layer_Name" at 577,-858.49 h60
M1 Board Outline:
  the board outline again, w10
  text ".Layer_Name" at 577,-858.49 h60
M2 Board Dimensions:
  rectangle: 0,-275 125,-150
  rectangle: 125,-400 500,-275
  lines w7: 0,-275 1000,-275 ; 125,-400 125,-150 ; 250,-400 250,-150 ; 500,-400 500,-150 ; 750,-400 750,-150 ; 0,-400 1000,-400 1000,-150 0,-150 0,-400
  text ".Layer_Name" at 577,-858.49 h60
M3 3D STEP Top:
  text ".Layer_Name" at 577,-858.49 h60
M4 3D STEP Bottom:
  text ".Layer_Name" at 577,-858.49 h60
M5 Assembly Top:
  lines w10: -292,-930.17 6308,-930.17 ; -292,-726.83 6310,-726.83 ; -292,-523.5 -292,-1133.5 3713,-1133.5 6310,-1133.5 6310,-523.5 -291.5,-523.5 -291.5,-1133.5 1284,-1133.5 ; 2173,-1133.5 2173,-523.5 ; 3440,-726.83 3440,-523.5 ; 4280,-726.83 4280,-523.5 ; 4902,-1140 4902,-937.17
  text "COMPONENTS MARKED 'DNP' SHOULD NOT BE POPULATED." at 1153.5,-318.5 h60
  text "ASSEMBLY VARIANT:" at 1153,-434 h60
  text ".VariantName" at 2189,-434 h60
  text "PCB VIEWED FROM TOP SIDE" at -228.5,-655.67 h60
  text "BOARD #:" at 2248,-655.67 h60
  text ".PRJ_Number" at 2793.5,-655.67 h60
  text "REV:" at 3638,-655.67 h60
  text ".PCB_Rev" at 3929.5,-655.67 h60
  text "SVN REV:" at 4476,-655.67 h60
  text ".VersionControl_RevNumber" at 4982,-655.67 h60
  text "TID #:" at 2248,-859 h60
  text ".TID" at 2793.5,-859 h60
  text "PLOT NAME =" at -228.5,-1064.34 h60
  text ".plot_File_Name" at 577,-1064.34 h60
  text "GENERATED    :" at 2250,-1064.34 h60
  text ".Print_Date" at 3119.5,-1064.34 h60
  text ".Print_Time" at 3848.5,-1064.34 h60
  text "TEXAS INSTRUMENTS" at 5113,-1064.34 h60
M6 Assembly Bottom:
  lines w10: -292.5,-727.33 6309.5,-727.33 ; -290.5,-930.67 6309.5,-930.67 ; 1115.5,-1140.5 1115.5,-937.67 ; 1737.5,-727.33 1737.5,-524 ; 2577.5,-727.33 2577.5,-524 ; 3844.5,-1134 3844.5,-524 ; 4733.5,-1134 6309,-1134 6309,-524 -292.5,-524 -292.5,-1134 2304.5,-1134 6309.5,-1134 6309.5,-524
  text "COMPONENTS MARKED 'DNP' SHOULD NOT BE POPULATED." at 6102,-318 h60
  text ".VariantName" at 5058,-434 h60
  text "ASSEMBLY VARIANT:" at 6097,-434 h60
  text ".VersionControl_RevNumber" at 1035.5,-656.17 h60
  text "SVN REV:" at 1541.5,-656.17 h60
  text ".PCB_Rev" at 2088,-656.17 h60
  text "REV:" at 2379.5,-656.17 h60
  text ".PRJ_Number" at 3224,-656.17 h60
  text "BOARD #:" at 3769.5,-656.17 h60
  text "PCB VIEWED FROM BOTTOM SIDE" at 6246,-656.17 h60
  text ".TID" at 3224,-859.5 h60
  text "TID #:" at 3769.5,-859.5 h60
  text "TEXAS INSTRUMENTS" at 904.5,-1064.84 h60
  text ".Print_Time" at 2169,-1064.84 h60
  text ".Print_Date" at 2898,-1064.84 h60
  text "GENERATED    :" at 3767.5,-1064.84 h60
  text ".plot_File_Name" at 5440.5,-1064.84 h60
  text "PLOT NAME =" at 6246,-1064.84 h60
M9 Title Sheet:
  drawing of 57 lines, arcs and shapes, not listed
  text "1" at 739.84,8036.5 h70
  text "2" at 3235.5,8036.5 h70
  text "3" at 5724.84,8036.5 h70
  text "4" at 8231.51,8036.5 h70
  text "5" at 10730.5,8036.5 h70
  text "6" at 13235.5,8036.5 h70
  text "A" at -416.5,6893.5 h70
  text "A" at 14383.5,6893.5 h70
  text "B" at -416.5,4513.5 h70
  text "B" at 14383.5,4513.5 h70
  text "C" at -416.5,2138.5 h70
  text "C" at 14383.5,2138.5 h70
  text "PROJECT TITLE:" at 11343.5,277.5 h45
  text ".PRJ_Title" at 11393.5,144.17 h70
  text "DESIGNED FOR:" at 11343.5,-23.5 h45
  text ".PRJ_Customer" at 11393.5,-163.5 h70
  text "D" at -416.5,-231.5 h70
  text "D" at 14383.5,-231.5 h70
  text "FILE NAME:" at 11343.5,-323.5 h45
  text ".PCB_File_Name_No_Path" at 11393.5,-443.5 h70
  text "Texas Instruments (TI) and/or its licensors do not warrant the accuracy or completeness of this specification" at 6374,-605.34 h45
  text "ENGINEER:" at 11343.5,-613.5 h45
  text "LAYOUT BY:" at 12848.5,-613.5 h45
  text "or any information contained therein. TI and/or its licensors do not warrant that this design will meet" at 6329.01,-718 h45
  text ".PRJ_Engineer" at 11393.5,-768.49 h70
  text ".PCB_Layout" at 12899,-768.49 h70
  text "the specifications, will be suitable for your application or fit for any particular purpose, or will operate in" at 6329.01,-830.67 h45
  text ".Layer_Name" at 577,-858.49 h60
  text "ALTIUM DESIGNER VERSION:" at 12848.5,-923.5 h45
  text "an implementation. TI and/or its licensors do not warrant that the design is production worthy. You should" at 6329.01,-943.33 h45
  text "completely validate and test your design implementation to confirm the system functionality for your application." at 6374,-1056 h45
  text ".print_Scale" at 11393.5,-1056.83 h70
  text ".Application_BuildNumber" at 12899,-1056.83 h70
  text "1" at 739.84,-1263.5 h70
  text "2" at 3235.5,-1263.5 h70
  text "3" at 5724.84,-1263.5 h70
  text "4" at 8231.51,-1263.5 h70
  text "5" at 10730.5,-1263.5 h70
  text "6" at 13235.5,-1263.5 h70
M10 Fab Notes:
  drawing of 189 lines, arcs and shapes, not listed
  text "DESIGN INFORMATION" at 12382.02,6356.17 h60
  text "MIN. TRACK WIDTH:" at 11737.46,6224.05 h60
  text "8" at 12833.7,6224.05 h60
  text "MIL" at 12988.46,6224.05 h60
  text "MIN. CLEARANCE:" at 11737.46,6099.92 h60
  text "0.2" at 12773.7,6099.93 h60
  text "mm" at 12988.46,6099.92 h60
  text "MIN. VIA PAD SIZE:" at 11737.46,5975.8 h60
  text "24" at 12803.71,5975.8 h60
  text "MIL" at 12988.46,5975.8 h60
  text "0.05mm (2MIL)" at 12432.46,5845.9 h60
  text "MINIMUM ANNULAR RING" at 11408.23,5837.67 h60
  text "EXTERNAL" at 13140.46,5837.67 h60
  text "PER" at 11608.23,5727.55 h60
  text "IPC-D-275 CLASS 2 LEVEL C" at 11828.23,5727.54 h60
  text "MIL, HOLES" at 13316.46,5627.07 h60
  text "+/-" at 12924,5618.48 h60
  text "+/-" at 13778,5618.48 h60
  text "REGISTRATION TOLERANCES:" at 11408.23,5617.42 h60
  text "METAL" at 12608,5617.42 h60
  text "5" at 13184.2,5617.42 h60
  text "3" at 14017.2,5617.42 h60
  text "MIL" at 14133.46,5617.42 h60
  text "HOLE SIZE TOLERANCE (UNLESS OTHERWISE SPECIFIED):" at 11408.23,5519.1 h60
  text "+/-" at 13778,5516.23 h60
  text "3" at 14017.2,5515.17 h60
  text "MIL" at 14133.46,5515.17 h60
  text "MATERIAL:" at 11333.46,5377.52 h60
  text "FR-4 High Tg" at 12319.9,5249 h60
  text "X" at 12175.46,5241.01 h60
  text "FR-408" at 11754.46,5236.49 h60
  text "OTHER" at 13242.46,5236.49 h60
  text "62 MIL (1.6mm) +/-10%" at 12074.56,5093.46 h60
  text "X" at 11954.46,5091.01 h60
  text "THICKNESS:" at 11408.23,5085.24 h60
  text "OTHER" at 13359.46,5085.24 h60
  text "TOLERANCE:" at 11408.23,4946.92 h60
  text "X" at 12256.46,4946.92 h60
  text "ANSI IPC-6012 TYPE 3 CLASS 2" at 12434.48,4946.92 h60
  text "OTHER +/-" at 12434.46,4802.73 h60
  text "BOW & TWIST:" at 11408.23,4657.54 h60
  text "X" at 12256.46,4657.54 h60
  text "ANSI IPC-6012 TYPE 3 CLASS 2" at 12434.48,4657.54 h60
  text "OTHER +/-" at 12434.46,4510.85 h60
  text "DRILLING:" at 11333.46,4380.23 h60
  text "NC_DRILL FILES" at 13094.46,4275.04 h60
  text "REFERENCE:" at 11408.23,4271.1 h60
  text "X" at 12065.46,4271.01 h60
  text "AS SHOWN" at 12243.46,4271.1 h60
  text "X" at 12966.46,4271.1 h60
  text "OTHER" at 13392.46,4128.85 h60
  text "PTH COPPER THICKNESS:" at 11407.91,4125.32 h60
  text "X" at 12547.14,4125.32 h60
  text "20-30 um" at 12675.14,4125.32 h60
  text "BOARD FINISH:" at 11333.46,3977.73 h60
  text "SILKSCREEN:" at 11488.68,3867.6 h60
  text "X" at 12446.46,3867.6 h60
  text "TOP" at 12563.46,3867.6 h60
  text "X" at 12956.46,3867.6 h60
  text "BOTTOM" at 13074.46,3867.6 h60
  text "SILKSCREEN COLOR:" at 11488.68,3712.41 h60
  text "X" at 12445.46,3712.41 h60
  text "WHITE" at 12563.46,3712.41 h60
  text "OTHER" at 13074.46,3712.41 h60
  text "X" at 12576.46,3568.96 h60
  text "GREEN" at 12694.46,3568.96 h60
  text "OTHER" at 13312.46,3568.96 h60
  text "SOLDER RESIST COLOR:" at 11488.68,3562.1 h60
  text "X" at 12576.46,3414.71 h60
  text "MATTE" at 12694.46,3414.71 h60
  text "SEMI-GLOSS" at 13312,3414.07 h60
  text "IMMERSION GOLD (ENIG)" at 12394.46,3241.94 h60
  text "ENEPIG" at 13732,3234.72 h60
  text "SURFACE FINISH:" at 11333.46,3233.72 h60
  text "X" at 12216.46,3233.72 h60
  text "IMM. TIN/SILVER OR EQUIV" at 11663,3096.4 h60
  text "OTHER" at 13094.46,3092.47 h60
  text "ARRAY/PANEL:" at 11333.46,2937.09 h60
  text "CUT AND TRIM PER M1 BOARD OUTLINE" at 12394.46,2928.87 h60
  text "N.C. ROUTE" at 12394.46,2792.9 h60
  text "X" at 13082.46,2792.9 h60
  text "V. SCORE" at 13260.46,2792.9 h60
  text "CERTIFICATION:" at 11333.46,2663.77 h60
  text "MATERIALS AND WORKMANSHIP FOR ALL PCBS" at 12058.46,2663.77 h60
  text "TO MEET OR EXCEED THE REQUIREMENTS OF:" at 12058.46,2569.71 h60
  text "X" at 11695.97,2441.08 h60
  text "ANSI IPC-A-600F CLASS ->" at 11823.96,2441.08 h60
  text "X" at 13471.97,2441.08 h60
  text "2" at 13581.96,2441.08 h60
  text "1" at 13266.96,2439.58 h60
  text "3" at 13935.96,2439.58 h60
  text "X" at 12507.97,2293.39 h60
  text "RoHS" at 12635.96,2293.39 h60
  text "OTHER" at 13280.36,2293.39 h60
  text "PER ORDER" at 13677.42,2293.39 h60
  text "ALL BOARDS MUST MEET OR EXCEED UL94-V0 REQUIREMENTS." at 11361,2139.57 h60
  text "PCB MUST BEAR THE UL94V-0 UL REGISTERED MATERIAL ID NUMBER" at 11361,2023.5 h60
  text "ADDITIONAL REQUIREMENTS:" at 11333.46,1854.08 h60
  text "MICROSECTION:" at 11408.23,1746.95 h60
  text "YES" at 12313.96,1746.95 h60
  text "REQUIRED" at 13175.46,1602.62 h60
  text "BARE BOARD ELEC. TEST:" at 11408.23,1599.76 h60
  text "NONE" at 12713.96,1599.76 h60
  text "X" at 13057.46,1599.76 h60
  text "PER ORDER" at 13767.46,1599.76 h60
  text "XX MIL VIAS REQUIRE NON-CONDUCTIVE FILL AND PLANARIZE" at 11576.38,1394.82 h59
  text "XX MIL VIAS REQUIRE CONDUCTIVE FILL AND PLANARIZE" at 11584.38,1290.84 h60
  text "OUTER XX MIL TRACES REQUIRE 50 OHM SINGLE-ENDED IMPEDANCE" at 11583.39,1127.46 h58
  text "LAYER 2 & 3 (INNER LAYERS) XX MIL WIDE, XX MIL SPACE / TRACES REQUIRE 100 OHM DIFFERENTIAL IMPEDANCE" at 11575.39,891.74 h60
  text ".Layer_Name" at 577,-858.49 h60
M11 Gerber Information:
  lines w10: -292,-930.17 6308,-930.17 ; -292,-726.83 6310,-726.83 ; -292,-523.5 -292,-1133.5 3713,-1133.5 6310,-1133.5 6310,-523.5 -291.5,-523.5 -291.5,-1133.5 1284,-1133.5 ; 2173,-1133.5 2173,-523.5 ; 3440,-726.83 3440,-523.5 ; 4280,-726.83 4280,-523.5 ; 4902,-1140 4902,-937.17
  text "ALL ARTWORK VIEWED FROM TOP SIDE" at -228.5,-655.67 h60
  text "BOARD #:" at 2248,-655.67 h60
  text ".PRJ_Number" at 2793.5,-655.67 h60
  text "REV:" at 3638,-655.67 h60
  text ".PCB_Rev" at 3929.5,-655.67 h60
  text "SVN REV:" at 4476,-655.67 h60
  text ".VersionControl_RevNumber" at 4982,-655.67 h60
  text "LAYER NAME =" at -228.5,-858.49 h60
  text "TID #:" at 2248,-859 h60
  text ".TID" at 2793.5,-859 h60
  text "PLOT NAME =" at -228.5,-1064.34 h60
  text ".plot_File_Name" at 577,-1064.34 h60
  text "GENERATED    :" at 2250,-1064.34 h60
  text ".Print_Date" at 3119.5,-1064.34 h60
  text ".Print_Time" at 3848.5,-1064.34 h60
  text "TEXAS INSTRUMENTS" at 5113,-1064.34 h60
M12 Stackup:
  drawing of 295 lines, arcs and shapes, not listed
  text "Layer" at 9811.59,7672.44 h60
  text "Name" at 10221.51,7672.44 h60
  text "Material" at 11161.25,7672.44 h60
  text "Thickness" at 12021.02,7672.44 h60
  text "Constant" at 12670.85,7672.44 h60
  text "Board Layer Stack" at 13240.71,7672.44 h60
  text "1" at 9811.59,7552.44 h60
  text "Top Overlay" at 10221.51,7552.44 h60
  text "2" at 9811.59,7432.44 h60
  text "Top Solder" at 10221.51,7432.44 h60
  text "Solder Resist" at 11161.25,7432.44 h60
  text "0.40mil" at 12021.02,7432.44 h60
  text "3.5" at 12670.85,7432.44 h60
  text "3" at 9811.59,7312.44 h60
  text "Top Layer" at 10221.51,7312.44 h60
  text "Copper" at 11161.25,7312.44 h60
  text "2.80mil" at 12021.02,7312.44 h60
  text "4" at 9811.59,7192.44 h60
  text "Dielectric 1" at 10221.51,7192.44 h60
  text "FR-4 High TG" at 11161.25,7192.44 h60
  text "12.00mil" at 12021.02,7192.44 h60
  text "4.2" at 12670.85,7192.44 h60
  text "5" at 9811.59,7072.44 h60
  text "Signal Layer 1" at 10221.51,7072.44 h60
  text "Copper" at 11161.25,7072.44 h60
  text "2.80mil" at 12021.02,7072.44 h60
  text "6" at 9811.59,6952.44 h60
  text "Dielectric2" at 10221.51,6952.44 h60
  text "FR-4 High TG" at 11161.25,6952.44 h60
  text "26.00mil" at 12021.02,6952.44 h60
  text "4.2" at 12670.85,6952.44 h60
  text "7" at 9811.59,6832.44 h60
  text "Signal Layer 2" at 10221.51,6832.44 h60
  text "Copper" at 11161.25,6832.44 h60
  text "2.80mil" at 12021.02,6832.44 h60
  text "8" at 9811.59,6712.44 h60
  text "Dielectric3" at 10221.51,6712.44 h60
  text "FR-4 High TG" at 11161.25,6712.44 h60
  text "12.00mil" at 12021.02,6712.44 h60
  text "4.2" at 12670.85,6712.44 h60
  text "9" at 9811.59,6592.44 h60
  text "Bottom Layer" at 10221.51,6592.44 h60
  text "Copper" at 11161.25,6592.44 h60
  text "2.80mil" at 12021.02,6592.44 h60
  text "10" at 9811.59,6472.44 h60
  text "Bottom Solder" at 10221.51,6472.44 h60
  text "Solder Resist" at 11161.25,6472.44 h60
  text "0.40mil" at 12021.02,6472.44 h60
  text "3.5" at 12670.85,6472.44 h60
  text "11" at 9811.59,6352.44 h60
  text "Bottom Overlay" at 10221.51,6352.44 h60
  text ".Layer_Name" at 577,-858.49 h60
M13 Component Bodies Top:
  text ".Layer_Name" at 577,-858.49 h60
M14 Component Bodies Bottom:
  text ".Layer_Name" at 577,-858.49 h60
M15 Courtyards Top:
  text ".Layer_Name" at 577,-858.49 h60
M16 Courtyards Bottom:
  text ".Layer_Name" at 577,-858.49 h60
Drill Drawing:
  circle w10: c5363.72,3273.62 r16.58
  circle w10: c5363.72,3273.62 r27.63
  circle w10: c5363.72,3149.3 r27.63
  lines w10: 5336.09,1878.47 5391.34,1878.47 5391.34,1933.73 5336.09,1933.73 5336.09,1878.47 ; 5336.09,2016.61 5349.9,2016.61 5349.9,2002.79 5377.53,2002.79 5377.53,2016.61 5391.34,2016.61 5391.34,2044.23 5377.53,2044.23 5377.53,2058.05 5349.9,2058.05 5349.9,2044.23 5336.09,2044.23 5336.09,2016.61 ; 5336.09,2127.11 5363.72,2140.93 5391.34,2127.11 5377.53,2154.74 5391.34,2182.37 5363.72,2168.55 5336.09,2182.37 5349.9,2154.74 5336.09,2127.11 ; 5336.09,2306.69 5391.34,2306.69 5363.72,2251.43 5336.09,2306.69 ; 5336.09,2403.38 5363.72,2375.75 5391.34,2403.38 5363.72,2431.01 5336.09,2403.38 ; 5336.09,2500.07 5391.34,2500.07 5391.34,2555.33 5336.09,2555.33 5336.09,2500.07 ; 5336.09,2624.39 5336.09,2638.21 5349.9,2652.02 5336.09,2665.83 5336.09,2679.65 5349.9,2679.65 5363.72,2665.83 5377.53,2679.65 5391.34,2679.65 5391.34,2665.83 5377.53,2652.02 5391.34,2638.21 5391.34,2624.39 5377.53,2624.39 5363.72,2638.21 5349.9,2624.39 5336.09,2624.39 ; 5336.09,2748.71 5363.72,2762.53 5391.34,2748.71 5377.53,2776.34 5391.34,2803.97 5363.72,2790.15 5336.09,2803.97 5349.9,2776.34 5336.09,2748.71 ; 5336.09,2886.85 5349.9,2886.85 5363.72,2873.03 5377.53,2886.85 5391.34,2886.85 5377.53,2900.66 5391.34,2914.47 5377.53,2914.47 5363.72,2928.29 5349.9,2914.47 5336.09,2914.47 5349.9,2900.66 5336.09,2886.85 ; 5336.09,3052.61 5391.34,3052.61 5363.72,2997.35 5336.09,3052.61 ; 5336.09,3384.13 5349.9,3384.13 5363.72,3370.31 5377.53,3384.13 5391.34,3384.13 5377.53,3397.94 5391.34,3411.75 5377.53,3411.75 5363.72,3425.57 5349.9,3411.75 5336.09,3411.75 5349.9,3397.94 5336.09,3384.13 ; 5347.14,2511.12 5380.29,2511.12 5380.29,2544.28 5347.14,2544.28 5347.14,2511.12 ; 5347.14,2759.76 5363.72,2768.05 5380.29,2759.76 5372.01,2776.34 5380.29,2792.92 5363.72,2784.63 5347.14,2792.92 5355.43,2776.34 5347.14,2759.76 ; 5347.14,2892.37 5355.43,2892.37 5363.72,2884.08 5372.01,2892.37 5380.29,2892.37 5372.01,2900.66 5380.29,2908.95 5372.01,2908.95 5363.72,2917.24 5355.43,2908.95 5347.14,2908.95 5355.43,2900.66 5347.14,2892.37 ; 5347.14,3041.56 5380.29,3041.56 5363.72,3008.4 5347.14,3041.56
  lines w12: 5286,1841.18 8517.49,1841.18 ; 5286,3457.34 8517.49,3457.34 ; 5623.86,1716.86 5623.86,3581.66 ; 5955.86,1716.86 5955.86,3581.66 ; 6592.43,1716.86 6592.43,3581.66 ; 6851.57,1716.86 6851.57,3581.66 ; 7226.72,1716.86 7226.72,3581.66 ; 7951.05,1716.86 7951.05,3581.66 ; 5286,1716.86 8517.49,1716.86 8517.49,3581.66 5286,3581.66 5286,1716.86
  text "Symbol" at 5360.59,3494.63 h72
  text "Quantity" at 5661.16,3494.63 h72
  text "Finished Hole Size" at 5993.16,3494.63 h72
  text "Plated" at 6629.72,3494.63 h72
  text "Hole Type" at 6888.86,3494.63 h72
  text "Drill Layer Pair" at 7264.02,3494.63 h72
  text "Hole Tolerance" at 7988.35,3494.63 h72
  text "1" at 5661.16,3370.31 h60
  text "23.62mil (0.600mm)" at 5993.16,3370.31 h60
  text "NPTH" at 6629.72,3370.31 h60
  text "Round" at 6888.86,3370.31 h60
  text "Top Layer - Bottom Layer" at 7264.02,3370.31 h60
  text "+/-1.18mil" at 7988.35,3370.31 h60
  text "10" at 5661.16,3245.99 h60
  text "7.87mil (0.200mm)" at 5993.16,3245.99 h60
  text "PTH" at 6629.72,3245.99 h60
  text "Round" at 6888.86,3245.99 h60
  text "Top Layer - Bottom Layer" at 7264.02,3245.99 h60
  text "448" at 5661.16,3121.67 h60
  text "10.00mil (0.254mm)" at 5993.16,3121.67 h60
  text "PTH" at 6629.72,3121.67 h60
  text "Round" at 6888.86,3121.67 h60
  text "Top Layer - Bottom Layer" at 7264.02,3121.67 h60
  text "24" at 5661.16,2997.35 h60
  text "11.81mil (0.300mm)" at 5993.16,2997.35 h60
  text "PTH" at 6629.72,2997.35 h60
  text "Round" at 6888.86,2997.35 h60
  text "Top Layer - Bottom Layer" at 7264.02,2997.35 h60
  text "12" at 5661.16,2873.03 h60
  text "15.00mil (0.381mm)" at 5993.16,2873.03 h60
  text "PTH" at 6629.72,2873.03 h60
  text "Round" at 6888.86,2873.03 h60
  text "Top Layer - Bottom Layer" at 7264.02,2873.03 h60
  text "4" at 5661.16,2748.71 h60
  text "39.37mil (1.000mm)" at 5993.16,2748.71 h60
  text "PTH" at 6629.72,2748.71 h60
  text "Round" at 6888.86,2748.71 h60
  text "Top Layer - Bottom Layer" at 7264.02,2748.71 h60
  text "19" at 5661.16,2624.39 h60
  text "40.00mil (1.016mm)" at 5993.16,2624.39 h60
  text "PTH" at 6629.72,2624.39 h60
  text "Round" at 6888.86,2624.39 h60
  text "Top Layer - Bottom Layer" at 7264.02,2624.39 h60
  text "2" at 5661.16,2500.07 h60
  text "43.31mil (1.100mm)" at 5993.16,2500.07 h60
  text "PTH" at 6629.72,2500.07 h60
  text "Round" at 6888.86,2500.07 h60
  text "Top Layer - Bottom Layer" at 7264.02,2500.07 h60
  text "4" at 5661.16,2375.75 h60
  text "49.21mil (1.250mm)" at 5993.16,2375.75 h60
  text "PTH" at 6629.72,2375.75 h60
  text "Round" at 6888.86,2375.75 h60
  text "Top Layer - Bottom Layer" at 7264.02,2375.75 h60
  text "1" at 5661.16,2251.43 h60
  text "19.69mil (0.500mm)" at 5993.16,2251.43 h60
  text "NPTH" at 6629.72,2251.43 h60
  text "Slot" at 6888.86,2251.43 h60
  text "Top Layer - Bottom Layer" at 7264.02,2251.43 h60
  text "+/-1.18mil" at 7988.35,2251.43 h60
  text "2" at 5661.16,2127.11 h60
  text "23.62mil (0.600mm)" at 5993.16,2127.11 h60
  text "PTH" at 6629.72,2127.11 h60
  text "Slot" at 6888.86,2127.11 h60
  text "Top Layer - Bottom Layer" at 7264.02,2127.11 h60
  text "+/-1.97mil" at 7988.35,2127.11 h60
  text "2" at 5661.16,2002.79 h60
  text "27.56mil (0.700mm)" at 5993.16,2002.79 h60
  text "PTH" at 6629.72,2002.79 h60
  text "Slot" at 6888.86,2002.79 h60
  text "Top Layer - Bottom Layer" at 7264.02,2002.79 h60
  text "+/-1.97mil" at 7988.35,2002.79 h60
  text "2" at 5661.16,1878.47 h60
  text "27.56mil (0.700mm)" at 5993.16,1878.47 h60
  text "PTH" at 6629.72,1878.47 h60
  text "Slot" at 6888.86,1878.47 h60
  text "Top Layer - Bottom Layer" at 7264.02,1878.47 h60
  text "+/-1.97mil" at 7988.35,1878.47 h60
  text "531 Total" at 5661.16,1754.15 h60
  text "Slot definitions :" at 5360.59,1667.13 h60
  text "Routed Path Length" at 5811.31,1667.13 h60
  text "= Calculated from tool start centre position to tool end centre position." at 6351.05,1667.13 h60
  text "Hole Length" at 5811.31,1617.4 h60
  text "= Routed Path Length + Tool Size = Slot length as defined in the PCB layout" at 6151.24,1617.4 h60
  text ".Layer_Name" at 577,-858.49 h60
M17 Embedded Cavity:
  text ".Layer_Name" at 577,-858.49 h60
M18 Embedded Assembly:
  text ".Layer_Name" at 577,-858.49 h60
M19 Embedded Keepout:
  text ".Layer_Name" at 577,-858.49 h60

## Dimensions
1492.13,2218.5 to 1492.13,765.75 on Top Overlay
386.81,765.75 to 1492.13,765.75 on Top Overlay
0,-400 to 1000,-400 on M2 Board Dimensions
0,0 to 0,3000 on M2 Board Dimensions
0,0 to 2000,0 on M2 Board Dimensions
